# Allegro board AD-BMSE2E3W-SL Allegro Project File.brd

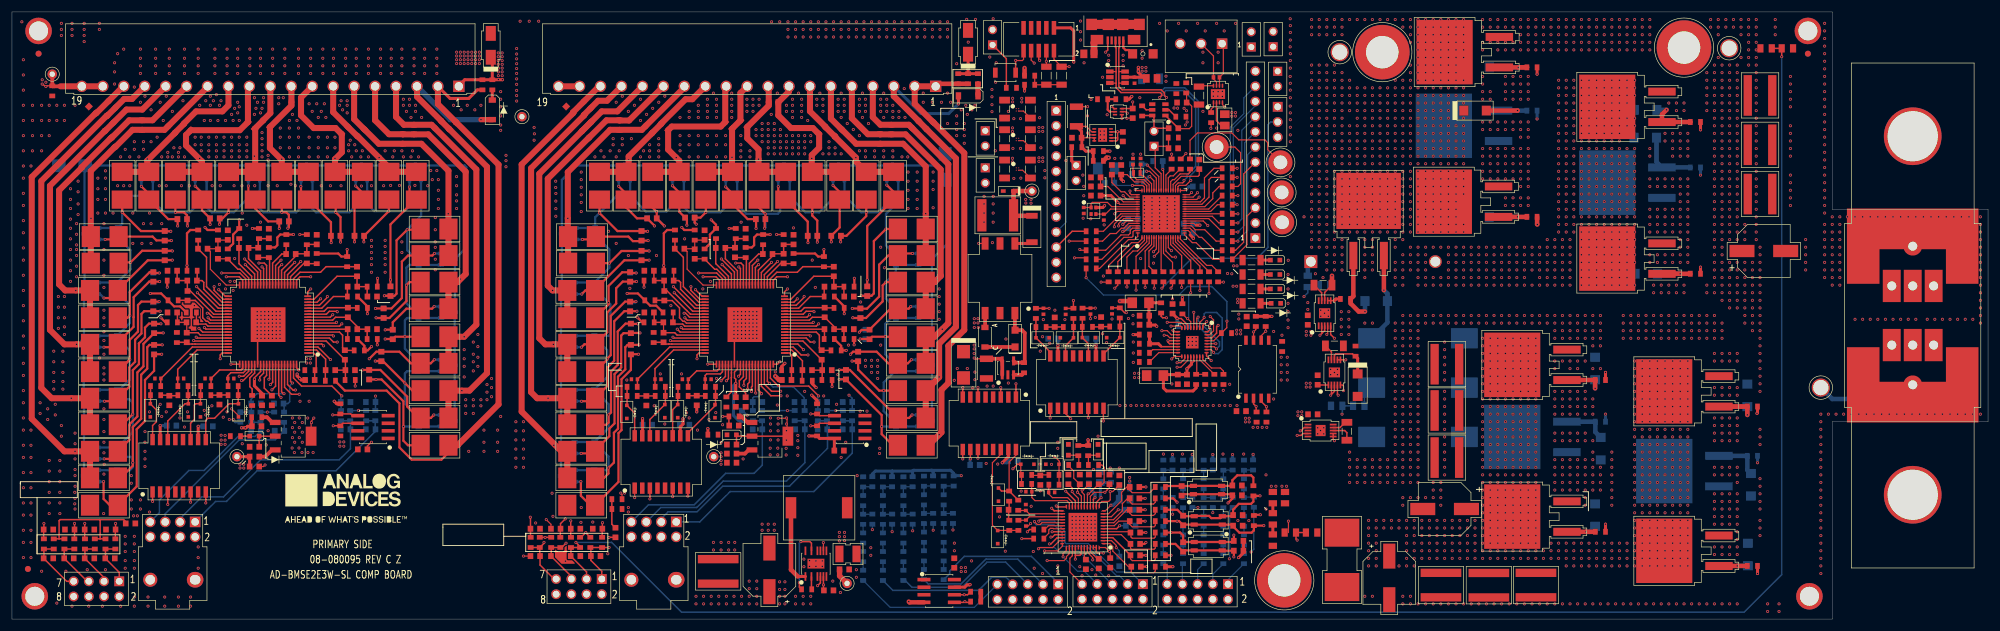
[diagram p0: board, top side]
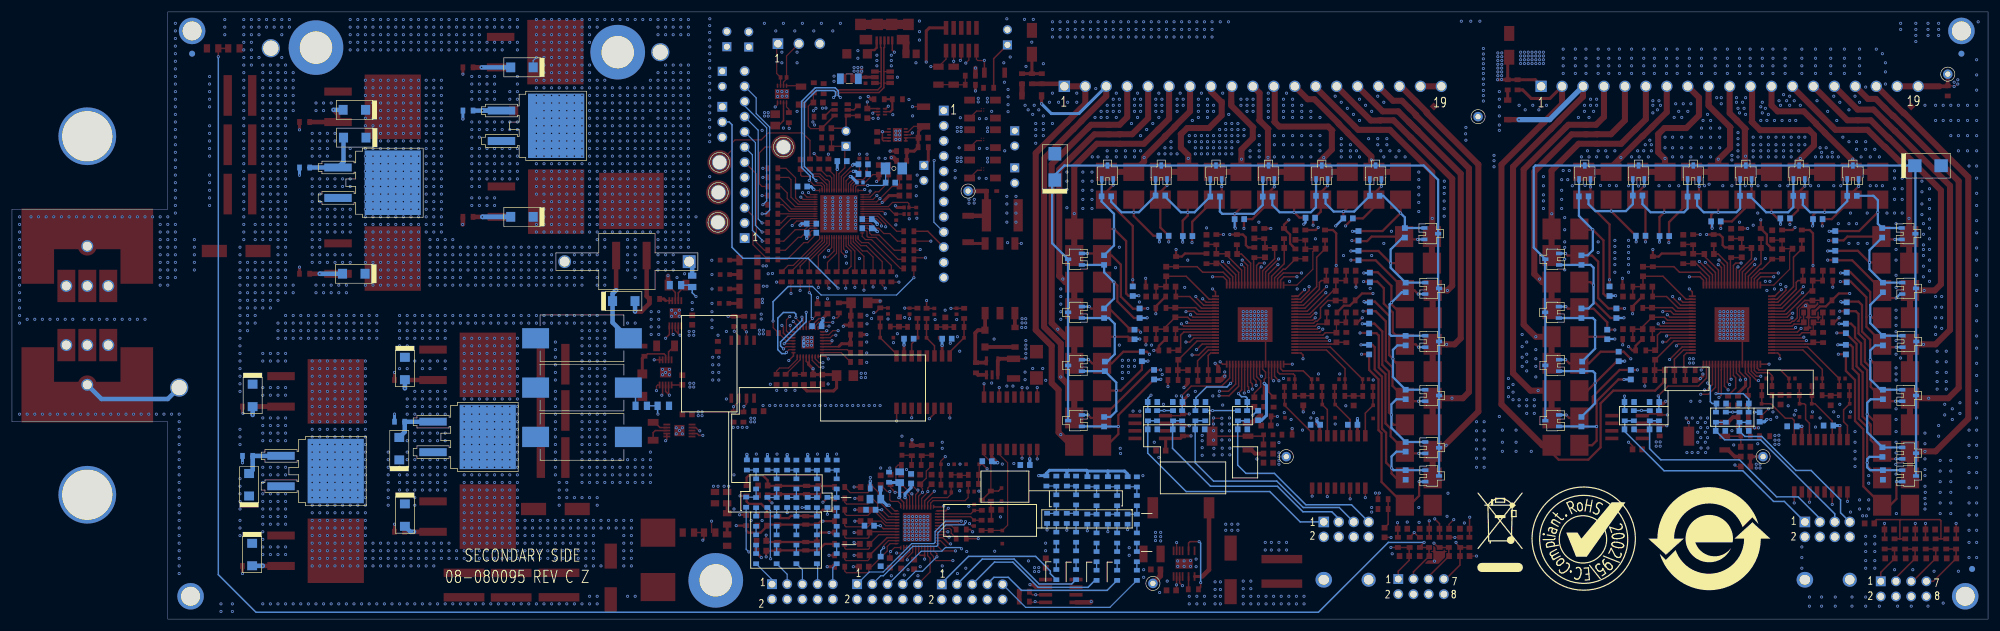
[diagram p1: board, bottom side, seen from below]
Outline 330.2 x 101.6 mm; copper layers: TOP, L2_GND, L3_SIGNAL, L4_POWER, L5_POWER, L6_SIGNAL, L7_GND, BOTTOM. Coordinates in mm from the lower left corner of the outline.
Outline path: 0,101.6 0,0 304.17,0 304.17,33.02 330.2,33.02 330.2,68.58 304.17,68.58 304.17,101.6 0,101.6

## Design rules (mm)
constraint set DEFAULT: min track width 0.203
net group USB: nets MCU_USB_DM MCU_USB_DP
net group 24MILS: nets 1V8_VDD 3V3_LDO 3V3_VDD BMS1_DRIVE BMS1_VREF2 BMS2_V- BMS2_VREF2 BMS2_VREG GND_ISO UNNAMED_16_ADP151V2_I3_VOUT VBAT+ VBUS

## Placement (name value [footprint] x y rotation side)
C1  10NF  [C0603]  73.62 82.57 225 top
C2  10NF  [C0603]  71.17 82.79 225.4 top
C3  10NF  [C0603]  67.18 81.91 270 top
C4  10NF  [C0603]  65.3 80.34 270.1 top
C5  10NF  [C0603]  58.33 81.37 225.4 top
C6  10NF  [C0603]  55.6 81.78 225.2 top
C7  10NF  [C0603]  47.5 86.49 180 top
C8  10NF  [C0603]  42.54 82.9 135.2 top
C9  10NF  [C0603]  53.21 41.66 0 top
C10  10NF  [C0603]  55.63 44.2 90 top
C11  10NF  [C0603]  56.9 48.51 0 top
C12  10NF  [C0603]  56.13 51.31 90 top
C13  10NF  [C0603]  56.9 55.63 0 top
C14  10NF  [C0603]  57.66 58.17 90 top
C15  10NF  [C0603]  49.28 60.32 90 top
C16  10NF  [C0603]  46.61 61.09 180 top
C17  0.22uF  [C0603]  59.69 40.89 90 top
C18  0.22uF  [C0603]  61.72 43.94 90 top
C19  0.22uF  [C0603]  63.63 47.62 90 top
C20  0.22uF  [C0603]  62.1 51.18 90 top
C21  0.22uF  [C0603]  63.25 54.86 90 top
C22  0.22uF  [C0603]  58.04 64.13 180 top
C23  0.22uF  [C0603]  54.1 64.13 180 top
C24  0.22uF  [C0603]  45.47 66.55 180 top
C25  10NF  [C0603]  40 82.61 135.1 top
C26  10NF  [C0603]  29.32 82.37 135.7 top
C27  10NF  [C0603]  26.67 81.91 135 top
C28  10NF  [C0603]  21.75 82.67 89.8 top
C29  10NF  [C0603]  16.09 81.14 135.1 top
C30  10NF  [C0603]  16.38 83.64 135 top
C31  10NF  [C0603]  16.72 86.15 135 top
C32  10NF  [C0603]  13.42 85.21 135 top
C33  10NF  [C0603]  41.15 61.34 90 top
C34  10NF  [C0603]  38.73 62.1 180 top
C35  10NF  [C0603]  34.42 61.09 90 top
C36  10NF  [C0603]  31.88 61.98 180 top
C37  10NF  [C0603]  30.1 56.64 180 top
C38  10NF  [C0603]  29.34 54.1 270 top
C39  10NF  [C0603]  29.97 49.66 180 top
C40  10NF  [C0603]  29.21 47.12 270 top
C41  0.22uF  [C0603]  33.91 67.06 180 top
C42  0.22uF  [C0603]  28.45 66.93 180 top
C43  0.22uF  [C0603]  25.53 64.13 270 top
C44  0.22uF  [C0603]  25.53 60.83 270 top
C45  0.22uF  [C0603]  23.62 57.28 270 top
C46  0.22uF  [C0603]  23.62 52.32 270 top
C47  0.22uF  [C0603]  23.75 48.64 270 top
C48  0.22uF  [C0603]  23.75 45.08 270 top
C49  0.22uF  [C0603]  67.95 33.02 90 bottom
C50  0.22uF  [C0603]  67.82 42.29 90 bottom
C51  0.22uF  [C0603]  67.95 51.18 90 bottom
C52  0.22uF  [C0603]  67.95 60.07 90 bottom
C53  0.22uF  [C0603]  67.56 70.74 180 bottom
C54  0.22uF  [C0603]  58.55 70.87 180 bottom
C55  0.22uF  [C0603]  49.4 70.7 180 bottom
C56  0.22uF  [C0603]  40.64 70.83 180 bottom
C57  0.22uF  [C0603]  31.74 70.83 180 bottom
C58  0.22uF  [C0603]  22.73 70.83 180 bottom
C59  0.22uF  [C0603]  17.69 64.64 270 bottom
C60  0.22uF  [C0603]  17.56 55.49 270 bottom
C61  0.22uF  [C0603]  17.56 46.6 270 bottom
C62  0.22uF  [C0603]  17.56 37.58 270 bottom
C63  0.22uF  [C0603]  17.65 27.94 270 bottom
C64  0.22uF  [C0603]  17.56 24.12 270 bottom
C65  1uF  [C0603]  43.43 36.58 270 top
C66  1uF  [C0603]  41.78 36.58 270 top
C67  10NF  [C0603]  49.78 40 180 top
C68  10NF  [C0603]  40.89 32.26 0 top
C69  0.1uF  [C0603]  58.6 28.4 0 top
C70  1uF  [C0603]  40.51 25.53 0 top
C71  0.1uF  [C0603]  59.94 36.32 180 bottom
C72  0.1uF  [C0603]  16.51 14.99 180 top
C73  0.1uF  [C0603]  55.75 36.32 0 bottom
C74  0.1uF  [C0603]  12.95 14.99 0 top
C75  0.1uF  [C0603]  44.58 36.07 180 bottom
C76  0.1uF  [C0603]  9.65 14.99 180 top
C77  0.1uF  [C0603]  40.77 36.07 0 bottom
C78  0.1uF  [C0603]  6.1 14.99 0 top
C79  10NF  [C0603]  59.94 31.75 180 bottom
C80  10NF  [C0603]  16.38 10.16 0 top
C81  10NF  [C0603]  55.75 31.75 180 bottom
C82  10NF  [C0603]  12.95 10.16 0 top
C83  10NF  [C0603]  44.7 31.5 180 bottom
C84  10NF  [C0603]  9.53 10.16 0 top
C85  10NF  [C0603]  40.77 31.5 180 bottom
C86  10NF  [C0603]  6.1 10.16 0 top
C87  300pF  [C0402]  24.38 40.26 180 top
C88  300pF  [C0402]  32.77 40.26 180 top
C89  300pF  [C0402]  28.19 40.26 0 top
C90  300pF  [C0402]  36.58 40.26 0 top
C91  0.1uF  [C0603]  26.29 36.58 270 top
C92  0.1uF  [C0603]  34.67 36.7 270 top
C93  10NF  [C0603]  26.67 32.38 0 bottom
C94  10NF  [C0603]  32.77 32.26 0 bottom
C95  10NF  [C0603]  153.38 82.57 225 top
C96  10NF  [C0603]  150.92 82.79 225.4 top
C97  10NF  [C0603]  146.94 81.91 270 top
C98  10NF  [C0603]  145.06 80.34 270.1 top
C99  10NF  [C0603]  138.09 81.37 225.4 top
C100  10NF  [C0603]  135.35 81.78 225.2 top
C101  10NF  [C0603]  127.25 86.49 180 top
C102  10NF  [C0603]  122.29 82.9 135.2 top
C103  10NF  [C0603]  132.88 41.66 0 top
C104  10NF  [C0603]  135.3 44.2 90 top
C105  10NF  [C0603]  136.57 48.51 0 top
C106  10NF  [C0603]  135.8 51.31 90 top
C107  10NF  [C0603]  136.57 55.63 0 top
C108  10NF  [C0603]  137.33 58.17 90 top
C109  10NF  [C0603]  128.95 60.32 90 top
C110  10NF  [C0603]  126.28 61.09 180 top
C111  0.22uF  [C0603]  139.36 40.89 90 top
C112  0.22uF  [C0603]  141.39 43.94 90 top
C113  0.22uF  [C0603]  143.3 47.62 90 top
C114  0.22uF  [C0603]  141.77 51.18 90 top
C115  0.22uF  [C0603]  142.92 54.86 90 top
C116  0.22uF  [C0603]  137.71 64.13 180 top
C117  0.22uF  [C0603]  133.77 64.13 180 top
C118  0.22uF  [C0603]  125.09 66.93 180 top
C119  10NF  [C0603]  119.75 82.61 135.1 top
C120  10NF  [C0603]  109.07 82.37 135.7 top
C121  10NF  [C0603]  106.43 81.91 135 top
C122  10NF  [C0603]  101.5 82.67 89.8 top
C123  10NF  [C0603]  95.85 81.14 135.1 top
C124  10NF  [C0603]  96.14 83.69 135 top
C125  10NF  [C0603]  96.12 86.05 135 top
C126  10NF  [C0603]  93.17 85.21 135 top
C127  10NF  [C0603]  120.82 61.34 90 top
C128  10NF  [C0603]  118.41 62.1 180 top
C129  10NF  [C0603]  114.09 61.09 90 top
C130  10NF  [C0603]  111.55 61.98 180 top
C131  10NF  [C0603]  109.77 56.64 180 top
C132  10NF  [C0603]  109.01 54.1 270 top
C133  10NF  [C0603]  109.64 49.66 180 top
C134  10NF  [C0603]  108.88 47.12 270 top
C135  0.22uF  [C0603]  113.28 67.18 180 top
C136  0.22uF  [C0603]  106.93 67.06 180 top
C137  0.22uF  [C0603]  105.2 64.13 270 top
C138  0.22uF  [C0603]  105.2 60.83 270 top
C139  0.22uF  [C0603]  103.29 57.28 270 top
C140  0.22uF  [C0603]  103.29 52.32 270 top
C141  0.22uF  [C0603]  103.42 48.64 270 top
C142  0.22uF  [C0603]  103.42 45.08 270 top
C143  0.22uF  [C0603]  147.7 33.02 90 bottom
C144  0.22uF  [C0603]  147.57 42.29 90 bottom
C145  0.22uF  [C0603]  147.7 51.18 90 bottom
C146  0.22uF  [C0603]  147.7 60.07 90 bottom
C147  0.22uF  [C0603]  147.32 70.74 180 bottom
C148  0.22uF  [C0603]  138.3 70.87 180 bottom
C149  0.22uF  [C0603]  129.16 70.7 180 bottom
C150  0.22uF  [C0603]  120.39 70.7 180 bottom
C151  0.22uF  [C0603]  111.5 70.83 180 bottom
C152  0.22uF  [C0603]  102.48 70.83 180 bottom
C153  0.22uF  [C0603]  97.45 64.64 270 bottom
C154  0.22uF  [C0603]  97.32 55.49 270 bottom
C155  0.22uF  [C0603]  97.32 46.6 270 bottom
C156  0.22uF  [C0603]  97.32 37.58 270 bottom
C157  0.22uF  [C0603]  97.32 28.82 270 bottom
C158  0.22uF  [C0603]  97.32 24.12 270 bottom
C159  1uF  [C0603]  122.6 36.32 270 top
C160  1uF  [C0603]  120.95 36.32 270 top
C161  10NF  [C0603]  129.45 40 180 top
C162  10NF  [C0603]  120.65 32.38 0 top
C163  0.1uF  [C0603]  138.22 28.19 0 top
C164  1uF  [C0603]  120.27 26.16 0 top
C165  0.1uF  [C0603]  139.61 36.32 180 bottom
C166  0.1uF  [C0603]  97.85 15.11 180 top
C167  0.1uF  [C0603]  135.42 36.32 0 bottom
C168  0.1uF  [C0603]  94.17 15.11 0 top
C169  0.1uF  [C0603]  131.56 36.32 180 bottom
C170  0.1uF  [C0603]  90.87 15.11 180 top
C171  0.1uF  [C0603]  124.58 36.32 0 bottom
C172  0.1uF  [C0603]  87.44 15.11 0 top
C173  10NF  [C0603]  139.61 31.75 180 bottom
C174  10NF  [C0603]  97.54 10.54 0 top
C175  10NF  [C0603]  135.42 31.75 180 bottom
C176  10NF  [C0603]  94.17 10.54 0 top
C177  10NF  [C0603]  131.69 31.75 180 bottom
C178  10NF  [C0603]  90.87 10.54 0 top
C179  10NF  [C0603]  124.58 31.75 180 bottom
C180  10NF  [C0603]  87.44 10.54 180 top
C181  10NF  [C0603]  45.47 66.55 180 bottom
C182  300pF  [C0402]  104.01 40.13 0 top
C183  300pF  [C0402]  112.52 40.13 0 top
C184  300pF  [C0402]  107.95 40.13 180 top
C185  0.1uF  [C0603]  106 36.54 270 top
C186  0.1uF  [C0603]  114.43 36.58 270 top
C187  10NF  [C0603]  106.17 32.51 0 bottom
C188  10NF  [C0603]  112.39 32.51 0 bottom
C189  10NF  [C0603]  58.04 64.13 180 bottom
C190  10NF  [C0603]  60.2 53.97 0 top
C191  10NF  [C0603]  60.2 48.51 0 top
C192  33NF  [C0805]  185.93 20.07 0 bottom
C193  33NF  [C0805]  181.86 23.75 270 bottom
C194  1uF  [C0603]  179.45 9.14 270 top
C195  1uF  [C0603]  179.96 23.49 90 bottom
C196  1uF  [C0603]  181.61 9.27 270 top
C197  22uF  [CPLSMSQ327H413]  126.57 8.23 90 top
C198  47NF  [C0603]  136.47 4.8 0 top
C199  1uF  [C1825H65]  118.01 7.98 90 top
C200  0.1uF  [C0603]  157.45 9.37 90 top
C201  100UF  [C1210H110]  139.7 10.9 0 top
C202  0.1uF  [C0603]  139.09 8.31 0 top
C203  300pF  [C0402]  169.42 18.67 90 top
C204  300pF  [C0402]  173.74 21.21 0 top
C205  300pF  [C0402]  169.44 16.06 270 top
C206  300pF  [C0402]  169.93 21.34 180 top
C207  0.1uF  [C0603]  165.74 18.29 180 top
C208  0.1uF  [C0603]  171.83 23.24 270 top
C209  10NF  [C0603]  167.26 26.42 0 bottom
C210  10NF  [C0603]  160.91 25.78 0 bottom
C211  0.1uF  [C0603]  205.41 34.8 180 top
C212  0.1uF  [C0603]  206.32 49.81 90 top
C214  4.7uF  [C1210H87]  162.84 41.91 270 top
C215  47UF  [C2220H98]  164.72 67.56 180 top
C216  10NF  [C0603]  173.96 46.91 180 bottom
C217  10NF  [C0603]  180.34 46.91 180 bottom
C218  0.1uF  [C0603]  174.24 49.68 90 top
C219  0.1uF  [C0603]  181.99 49.73 90 top
C220  300pF  [C0402]  172.36 51.51 270 top
C221  300pF  [C0402]  180.21 51.54 270 top
C222  300pF  [C0402]  176.07 51.49 270 top
C223  300pF  [C0402]  183.82 51.56 270 top
C224  0.1uF  [C0603]  189.23 49.25 180 top
C225  0.1uF  [C0603]  196.34 40.11 270 top
C226  0.1uF  [C0603]  189.23 50.77 180 top
C227  0.1uF  [C0603]  194.82 40.11 270 top
C228  0.1uF  [C0603]  193.93 51.92 90 top
C229  0.1uF  [C0603]  195.71 49.02 0 bottom
C230  22uF  [CPLSMSQ327H413]  230.15 6.88 270 top
C231  1uF  [C0603]  216.54 50.04 90 top
C232  1uF  [C1825H65]  238.79 5.69 270 top
C233  1uF  [C1825H65]  246.79 5.66 270 top
C234  0.1uF  [C1206]  223.06 31.42 270 top
C235  1uF  [C1825H65]  254.66 5.69 270 top
C236  22uF  [CPLSMSQ327H413]  239.4 18.41 180 top
C237  1uF  [C0603]  217.37 34.26 0 top
C238  1uF  [C1825H65]  239.78 34.9 180 top
C239  1uF  [C1825H65]  239.78 42.65 180 top
C240  0.1uF  [C1206]  219.08 55.88 0 top
C241  1uF  [C1825H65]  239.78 27.03 180 top
C242  22uF  [CPLSMSQ327H413]  292.74 61.59 0 top
C243  1uF  [C0603]  218.19 40 90 top
C244  1uF  [C1825H65]  292.1 79.38 0 top
C245  1uF  [C1825H65]  292.1 87.63 0 top
C246  1uF  [C1825H65]  292.1 71.12 0 top
C247  0.1uF  [C1206]  220.98 45.72 0 top
C248  0.1uF  [C0603]  187.27 84.63 90 top
C249  10uF  [C0603]  185.62 80.72 270 top
C250  0.047uF  [C1210H87]  177.88 84.1 270 top
C251  10uF  [C0603]  177.93 80.54 180 top
C252  1uF  [C1206]  165.86 85.34 270 top
C253  1uF  [C1206]  165.86 80.39 270 top
C254  1uF  [C1206]  165.86 75.31 270 top
C255  1uF  [C1206]  170.18 85.34 270 top
C256  1uF  [C1206]  170.18 80.39 270 top
C257  1uF  [C1206]  170.18 75.31 270 top
C258  0.1uF  [C0603]  183.52 9.4 270 top
C259  0.1uF  [C0603]  183.39 23.37 90 top
C260  0.1uF  [C0603]  185.04 9.65 270 bottom
C261  0.1uF  [C0603]  181.61 23.37 90 top
C262  0.1uF  [C0603]  186.69 18.29 0 bottom
C263  0.1uF  [C0603]  185.04 23.24 90 top
C264  0.1uF  [C0603]  179.96 23.37 90 top
C265  0.1uF  [C0603]  178.44 23.37 90 top
C266  0.1uF  [C0603]  186.94 15.62 0 bottom
C267  0.1uF  [C0603]  176.53 23.37 90 top
C268  2.2uF  [C0805H53]  202.67 83.54 90 top
C269  1uF  [C0603]  181.1 72.39 180 top
C270  0.1uF  [C0603]  181.1 73.91 180 top
C271  0.1uF  [C0603]  181.1 70.87 180 top
C272  1uF  [C0603]  198.4 76.1 90 top
C273  1uF  [C0603]  185.34 75.18 90 top
C274  4.7NF  [C0402]  188.49 73.08 0 bottom
C275  1uF  [C0603]  183.41 73.02 0 bottom
C276  1uF  [C0603]  191.49 76.63 180 bottom
C277  1uF  [C0603]  187.96 76.1 180 bottom
C278  1uF  [C0603]  198.12 72.39 0 bottom
C279  1uF  [C0603]  187.93 74.47 180 bottom
C280  10uF  [C1206H71]  182.83 75.41 0 bottom
C281  1uF  [C0603]  196.6 66.17 0 bottom
C282  1uF  [C0603]  196.6 64.64 0 bottom
C283  1uF  [C0603]  187.33 66.93 180 bottom
C284  1uF  [C0603]  187.33 65.4 180 bottom
C285  1uF  [C0603]  183.79 75.18 270 top
C286  1uF  [C0603]  194.06 78.79 0 top
C287  0.1uF  [C1206]  190.27 90.42 180 bottom
C288  1UF  [C0805H55]  190.45 90.47 180 top
C289  0.1uF  [C0603]  194.09 82.14 180 top
C290  10NF  [C0402]  187.58 90.17 90 top
C291  0.1uF  [C0603]  195.49 86.44 180 top
C292  12pF  [C0402]  188.6 76.58 270 top
C293  12pF  [C0402]  179.1 68.38 90 top
C294  12pF  [C0402]  187.33 76.58 270 top
C295  12pF  [C0402]  182.45 67.26 90 top
C296  10NF  [C0603]  63.63 47.62 90 bottom
C297  10NF  [C0603]  62.1 51.18 90 bottom
C298  10NF  [C0603]  59.69 40.89 90 bottom
C299  10NF  [C0603]  56.52 41.66 0 top
C300  10NF  [C0603]  61.72 43.94 90 bottom
C301  10NF  [C0603]  63.25 54.86 90 bottom
C302  10NF  [C0603]  50.93 63.5 90 top
C303  10NF  [C0603]  54.08 64.1 180 bottom
C304  10NF  [C0603]  26.8 51.31 180 top
C305  10NF  [C0603]  23.75 45.08 270 bottom
C306  10NF  [C0603]  25.53 60.83 270 bottom
C307  10NF  [C0603]  36.07 64.26 90 top
C308  10NF  [C0603]  25.53 64.13 270 bottom
C309  10NF  [C0603]  23.75 48.64 270 bottom
C310  10NF  [C0603]  23.62 52.2 270 bottom
C311  10NF  [C0603]  26.8 58.29 180 top
C312  10NF  [C0603]  28.45 66.93 180 bottom
C313  10NF  [C0603]  23.62 57.15 270 bottom
C314  10NF  [C0603]  42.93 64.52 90 top
C315  10NF  [C0603]  33.91 67.06 180 bottom
C316  10NF  [C0603]  40.51 28.83 0 top
C317  10NF  [C0603]  139.36 40.89 90 bottom
C318  10NF  [C0603]  136.19 41.66 0 top
C319  10NF  [C0603]  141.39 43.94 90 bottom
C320  10NF  [C0603]  139.87 48.51 0 top
C321  10NF  [C0603]  141.77 51.18 90 bottom
C322  10NF  [C0603]  133.75 64.1 180 bottom
C323  10NF  [C0603]  130.6 63.5 90 top
C324  10NF  [C0603]  125.09 66.93 180 bottom
C325  10NF  [C0603]  142.92 54.86 90 bottom
C326  10NF  [C0603]  139.87 53.97 0 top
C327  10NF  [C0603]  137.71 64.13 180 bottom
C328  10NF  [C0603]  142.62 47.62 90 bottom
C329  10NF  [C0603]  113.25 67.15 180 bottom
C330  10NF  [C0603]  122.6 64.52 90 top
C331  10NF  [C0603]  106.93 67.06 180 bottom
C332  10NF  [C0603]  103.29 52.2 270 bottom
C333  10NF  [C0603]  106.47 51.31 180 top
C334  10NF  [C0603]  103.42 45.08 270 bottom
C335  10NF  [C0603]  105.2 64.13 270 bottom
C336  300pF  [C0402]  116.33 40.13 180 top
C337  10NF  [C0603]  103.29 57.15 270 bottom
C338  10NF  [C0603]  106.47 58.29 180 top
C339  10NF  [C0603]  103.42 48.64 270 bottom
C340  10NF  [C0603]  115.74 64.26 90 top
C341  10NF  [C0603]  105.2 60.83 270 bottom
C342  10NF  [C0603]  120.27 29.21 0 top
C343  0.22uF  [C0603]  187.71 12.57 180 top
C344  0.22uF  [C0603]  187.58 22.1 180 top
C345  0.22uF  [C0603]  187.58 18.29 180 top
C346  0.22uF  [C0603]  204.85 17.4 0 top
C347  0.22uF  [C0603]  204.72 22.35 180 top
C348  0.22uF  [C0603]  204.98 11.43 0 top
C349  0.22uF  [C0603]  195.45 21.46 90 top
C350  0.22uF  [C0603]  195.71 16.51 90 top
C351  0.22uF  [C0603]  195.71 12.06 270 top
C352  0.22uF  [C0603]  204.98 13.08 0 top
C353  0.22uF  [C0603]  204.72 20.7 180 top
C354  0.22uF  [C0603]  204.85 15.62 0 top
C355  0.22uF  [C0603]  187.83 8.76 180 top
C356  0.22uF  [C0603]  187.58 16.38 180 top
C357  0.22uF  [C0603]  187.71 10.67 180 top
C358  0.22uF  [C0603]  187.58 20.19 180 top
C359  0.22uF  [C0603]  187.71 14.48 180 top
D1  SD12C-01FTG  [SOD323-5]  23.11 34.92 90 top
D2  SD12C-01FTG  [SOD323-5]  31.5 34.92 90 top
D3  SD12C-01FTG  [SOD323-5]  29.46 34.92 90 top
D4  SD12C-01FTG  [SOD323-5]  37.85 34.92 90 top
D5  SD12C-01FTG  [SOD323-5]  102.74 34.67 90 top
D6  SD12C-01FTG  [SOD323-5]  111.25 34.8 90 top
D7  SD12C-01FTG  [SOD323-5]  109.09 34.8 90 top
D8  SD12C-01FTG  [SOD323-5]  117.47 34.8 90 top
D9  SD12C-01FTG  [SOD323-5]  164.85 20.83 90 top
D10  SD12C-01FTG  [SOD323-5]  173.86 25.91 0 top
D11  SD12C-01FTG  [SOD323-5]  164.72 13.72 90 top
D12  SD12C-01FTG  [SOD323-5]  169.67 25.91 180 top
D13  SD12C-01FTG  [SOD323-5]  172.21 47.07 180 top
D14  SD12C-01FTG  [SOD323-5]  179.96 47.09 180 top
D15  SD12C-01FTG  [SOD323-5]  176.28 47.07 0 top
D16  SD12C-01FTG  [SOD323-5]  184.02 47.09 0 top
D17  TPSMF4L28A  [SOD123FL]  162.59 47.17 90 top
D18  PMEG10010ELRX  [SOD123F]  167.61 46.94 90 top
D19  PMEG6030EP,115  [SOD128]  170.43 65.28 270 top
D20  EDZVFHT2R15B  [SOD523_B]  166.5 71.63 180 top
D21  1N4148W-7-F  [SOD123-2]  80.26 85.22 270 top
D22  SMAT70A-13-F  [SMA-2]  80.01 96.01 90 top
D23  SMAT70A-13-F  [SMA-2]  159.77 96.52 90 top
D24  1N4148W-7-F  [SOD123-2]  159.79 87.55 180 top
D25  SBAV70LT3G  [SOT23_B]  40.46 74.75 180 bottom
D26  SBAV70LT3G  [SOT23_B]  49.25 74.75 180 bottom
D27  SBAV70LT3G  [SOT23_B]  58.39 74.75 180 bottom
D28  SBAV70LT3G  [SOT23_B]  67.39 74.75 180 bottom
D29  SBAV70LT3G  [SOT23_B]  72.82 60.22 90 bottom
D30  SBAV70LT3G  [SOT23_B]  72.87 51.33 90 bottom
D31  SBAV70LT3G  [SOT23_B]  72.82 42.44 90 bottom
D32  SBAV70LT3G  [SOT23_B]  72.82 33.2 90 bottom
D33  SMBJ75A-13-F  [DO214AA_A]  10.03 75.87 180 bottom
D34  SBAV70LT3G  [SOT23_B]  13.18 55.35 270 bottom
D35  SBAV70LT3G  [SOT23_B]  13.13 46.46 270 bottom
D36  SBAV70LT3G  [SOT23_B]  13.18 23.95 270 bottom
D37  SBAV70LT3G  [SOT23_B]  31.57 74.75 180 bottom
D38  SBAV70LT3G  [SOT23_B]  22.58 74.75 180 bottom
D39  SBAV70LT3G  [SOT23_B]  13.18 37.41 270 bottom
D40  SBAV70LT3G  [SOT23_B]  13.28 64.49 270 bottom
D41  SBAV70LT3G  [SOT23_B]  13.18 27.76 270 bottom
D42  SBAV70LT3G  [SOT23_B]  120.22 74.75 180 bottom
D43  SBAV70LT3G  [SOT23_B]  129.01 74.75 180 bottom
D44  SBAV70LT3G  [SOT23_B]  138.15 74.75 180 bottom
D45  SBAV70LT3G  [SOT23_B]  147.14 74.75 180 bottom
D46  SBAV70LT3G  [SOT23_B]  152.58 60.22 90 bottom
D47  SBAV70LT3G  [SOT23_B]  152.58 51.33 90 bottom
D48  SBAV70LT3G  [SOT23_B]  152.58 42.44 90 bottom
D49  SBAV70LT3G  [SOT23_B]  152.58 33.2 90 bottom
D50  SMBJ75A-13-F  [DO214AA_A]  155.93 75.67 90 bottom
D51  SBAV70LT3G  [SOT23_B]  92.89 55.35 270 bottom
D52  SBAV70LT3G  [SOT23_B]  92.89 23.95 270 bottom
D53  SBAV70LT3G  [SOT23_B]  111.33 74.75 180 bottom
D54  SBAV70LT3G  [SOT23_B]  92.89 46.46 270 bottom
D55  SBAV70LT3G  [SOT23_B]  92.89 28.68 270 bottom
D56  SBAV70LT3G  [SOT23_B]  102.34 74.75 180 bottom
D57  SBAV70LT3G  [SOT23_B]  93.04 64.49 270 bottom
D58  SBAV70LT3G  [SOT23_B]  92.89 37.41 270 bottom
D59  SMAJ7.0A  [DO214AC_A]  265.49 28.52 90 bottom
D60  SMAJ7.0A  [DO214AC_A]  264.54 17.4 270 bottom
D61  SMAJ7.0A  [DO214AC_A]  227.97 53.21 180 bottom
D62  SMAJ7.0A  [DO214AC_A]  264.54 41.93 270 bottom
D63  SMAJ7.0A  [DO214AC_A]  244.98 67.31 0 bottom
D64  SMAJ7.0A  [DO214AC_A]  244.48 85.09 0 top
D65  SMAJ7.0A  [DO214AC_A]  244.98 92.33 0 bottom
D66  SMBJ75A-13-F  [DO214AA_A]  159 42.54 270 top
D67  30KPA120CA  [DTH819L350W350LD52_BIDIR]  217.04 59.82 0 bottom
D68  SMAJ7.0A  [DO214AC_A]  289.98 37.43 270 bottom
D69  SMAJ7.0A  [DO214AC_A]  290.58 22.48 90 bottom
D70  SMAJ7.0A  [DO214AC_A]  290.07 10.79 270 bottom
D71  SMAJ7.0A  [DO214AC_A]  272.92 80.57 0 bottom
D72  SMAJ7.0A  [DO214AC_A]  272.98 85.22 0 bottom
D73  SMAJ7.0A  [DO214AC_A]  273.08 57.78 0 bottom
D74  SMAJ7.0A  [DO214AC_A]  224.87 39.14 270 top
DS1  SML-D13FWT86C  [LED0603-2]  40.51 30.61 180 top
DS2  SML-D13FWT86C  [LED0603-2]  120.27 30.84 180 top
DS3  SML-D13FWT86C  [LED0603-2]  211.07 60.07 180 top
DS4  SML-D13FWT86C  [LED0603-2]  211.07 57.66 180 top
DS5  SML-D13FWT86C  [LED0603-2]  211.2 52.83 180 top
DS6  SML-D13FWT86C  [LED0603-2]  211.07 55.24 180 top
E1  2.2KOHM AT 100MEGHZ  [L0603]  40.51 27.18 180 top
E2  2.2KOHM AT 100MEGHZ  [L0603]  38.17 33.81 90 bottom
E3  2.2KOHM AT 100MEGHZ  [L0603]  19.81 16 180 top
E4  2.2KOHM AT 100MEGHZ  [L0603]  120.27 27.69 180 top
E5  2.2KOHM AT 100MEGHZ  [L0603]  121.98 34.06 90 bottom
E6  2.2KOHM AT 100MEGHZ  [L0603]  100.84 14.48 270 top
E7  1KOHM AT 100MEGHZ  [L1206-3]  188.6 52.93 0 top
E8  1KOHM AT 100MEGHZ  [L1206-3]  191.01 40.74 0 top
F1  100A  [FSML484W177H185]  222.25 9.91 90 top
L1  220UH  [LSML402W394H201]  134.87 18.62 0 top
L2  2000OHMS  [L1206]  188.98 94.59 180 top
L3  4.7uH  [L0805]  179.96 94.59 0 top
L4  200UH  [LSML177W126H114]  199.77 21.59 0 top
L5  200UH  [LSML177W126H114]  199.9 16.51 0 top
L6  200UH  [LSML177W126H114]  199.9 12.19 180 top
NOREF  -  []  -221.61 -349.88 0 top
NOREF#2  -  []  304.17 0 90 top
NOREF#3  -  []  311.12 68.58 90 top
NOREF#4  -  []  55.24 20.19 0 top
NOREF#5  -  []  -221.61 -349.88 0 top
NOREF#6  -  []  0 65.24 0 top
NOREF#7  -  []  124.46 -78.61 0 top
NOREF#8  -  []  0 0 0 top
NOREF#9  -  []  304.17 81.48 0 top
NOREF#10  -  [unnamed#2]  300.1 94.62 0 top
NOREF#11  -  []  -144.14 127 0 top
NOREF#12  -  []  -1.65 -30.35 0 top
NOREF#13  -  [unnamed#2]  300.1 98.43 0 top
NOREF#14  -  [unnamed#2]  4.45 98.43 0 top
NOREF#15  -  []  132.08 160.02 0 top
NOREF#16  -  []  4.79 0 90 top
NOREF#17  -  []  301.94 0 90 top
NOREF#18  -  []  202.99 100.96 0 top
NOREF#19  -  []  304.17 101.6 180 top
NOREF#20  -  [unnamed#2]  2.67 8.38 0 top
NOREF#21  -  []  328.17 33.02 90 top
NOREF#22  -  []  -140.44 104.14 0 top
NOREF#23  -  [unnamed#2]  4.45 94.62 0 top
NOREF#24  -  [unnamed#2]  3.81 3.81 0 top
NOREF#25  -  []  330.2 33.02 90 top
NOREF#26  -  []  -221.61 -349.88 0 top
NOREF#27  -  []  -140.39 81.28 0 top
NOREF#28  -  []  90.68 112.27 0 top
NOREF#29  -  []  330.2 68.58 180 top
NOREF#30  -  []  0 101.6 270 top
NOREF#31  -  []  0 101.13 0 top
NOREF#32  -  [unnamed#2]  300.36 3.81 0 top
NOREF#33  -  [unnamed#2]  4.45 94.62 180 bottom
NOREF#34  -  []  72.26 24.76 180 bottom
NOREF#35  -  [unnamed#2]  2.67 8.38 180 bottom
NOREF#36  -  []  67.56 13.33 180 bottom
NOREF#37  -  []  46.61 13.46 180 bottom
NOREF#38  -  [unnamed#2]  300.1 94.62 180 bottom
P1  1841800000  [CNTHMHDRRA1X19L2673W437H295]  74.68 89.15 180 top
P2  1053141308  [CNMOLEX1053141308]  30.61 16.26 180 top
P3  TSW-104-07-G-D  [CNTHMHDR2X4L400W200H330]  17.92 6.32 180 top
P4  1841800000  [CNTHMHDRRA1X19L2673W437H295]  154.35 89.15 180 top
P5  1053141308  [CNMOLEX1053141308]  111 16.26 180 top
P6  TSW-104-07-G-D  [CNTHMHDR2X4L400W200H330]  98.55 6.7 180 top
P7  TSW-105-08-G-D  [CNSAMTEC2X5H338LD36]  203.2 5.84 180 top
P8  TSW-105-08-G-D  [CNSAMTEC2X5H338LD36]  174.82 5.81 180 top
P9  TSW-105-08-G-D  [CNSAMTEC2X5H338LD36]  188.98 5.84 180 top
P10  OSTTF030161  [CNOSTTF030161]  202.21 96.29 180 top
P11  ZX62-AB-5PA(31)  [CNHRSZX62-B-5PA_6SHLD]  184.4 99.51 180 top
P12  3220-10-0300-00  [CNSMMHDR2X5L443W201H228]  171.58 97.03 180 top
P13  TSW-112-16-G-S  [CNHDR1X12H420]  207.77 63.75 90 top
P14  TSW-112-16-G-S  [CNHDR1X12H420]  174.5 85.09 270 top
P15  69157-102HLF  [CNBERG69157-102]  207.09 95.73 90 top
P16  69157-102HLF  [CNBERG69157-102]  177.83 75.92 270 top
P17  69157-102HLF  [CNBERG69157-102]  162.64 75.51 270 top
P18  69157-102HLF  [CNBERG69157-102]  162.64 81.71 270 top
P19  69157-102HLF  [CNBERG69157-102]  163.86 96.09 90 top
P20  M20-9990345  [CNHDR1X3H340]  211.51 85.72 270 top
P21  69157-102HLF  [CNBERG69157-102]  211.51 91.67 270 top
P22  69157-102HLF  [CNBERG69157-102]  210.74 95.78 90 top
P23  69157-102HLF  [CNBERG69157-102]  190.83 79.12 90 top
Q1  BCP56-16TF  [SOT223_A]  46.99 30.61 270 top
Q2  BCP56-16TF  [SOT223_A]  126.66 30.61 270 top
Q3  IPB048N15N5LFATMA1  [TO263-3]  255.27 30.48 270 bottom
Q4  IPB048N15N5LFATMA1  [TO263-3]  255.27 17.14 90 top
Q5  IPB048N15N5LFATMA1  [TO263-3]  243.84 69.85 90 top
Q6  IPB048N15N5LFATMA1  [TO263-3]  255.27 42.54 90 top
Q7  IPB048N15N5LFATMA1  [TO263-3]  226.7 65.4 0 top
Q8  IPB048N15N5LFATMA1  [TO263-3]  243.84 82.55 270 bottom
Q9  IPB048N15N5LFATMA1  [TO263-3]  243.97 94.87 90 top
Q10  IPB048N15N5LFATMA1  [TO263-3]  280.67 38.1 90 top
Q11  IPB048N15N5LFATMA1  [TO263-3]  280.67 24.76 270 bottom
Q12  IPB048N15N5LFATMA1  [TO263-3]  280.67 11.43 90 top
Q13  IPB048N15N5LFATMA1  [TO263-3]  271.15 73.02 270 bottom
Q14  IPB048N15N5LFATMA1  [TO263-3]  271.15 85.72 90 top
Q15  IPB048N15N5LFATMA1  [TO263-3]  271.15 60.32 90 top
R1  200  [R0603]  80.26 89.41 90 top
R2  200  [R0603]  53.21 39.88 180 top
R3  200  [R0603]  56.52 40 180 top
R4  200  [R0603]  58.04 44.96 180 top
R5  200  [R0603]  56.9 46.86 180 top
R6  200  [R0603]  60.2 46.86 180 top
R7  200  [R0603]  58.55 52.07 180 top
R8  200  [R0603]  56.9 53.97 180 top
R9  200  [R0603]  60.2 55.63 180 top
R10  200  [R0603]  56.01 59.82 270 top
R11  200  [R0603]  50.93 60.32 270 top
R12  200  [R0603]  49.28 63.5 270 top
R13  200  [R0603]  45.85 63.5 270 top
R14  15  [R2512-2]  70.61 29.08 180 top
R15  15  [R2512-2]  70.61 33.65 180 top
R16  15  [R2512-2]  70.61 38.23 180 top
R17  15  [R2512-2]  70.61 42.8 180 top
R18  15  [R2512-2]  70.61 47.24 180 top
R19  15  [R2512-2]  70.61 51.94 180 top
R20  15  [R2512-2]  70.61 56.39 180 top
R21  15  [R2512-2]  70.61 60.83 180 top
R22  15  [R2512-2]  70.61 65.28 180 top
R23  15  [R2512-2]  67.56 72.52 270 top
R24  15  [R2512-2]  62.99 72.52 270 top
R25  15  [R2512-2]  58.55 72.52 270 top
R26  15  [R2512-2]  53.98 72.52 270 top
R27  15  [R2512-2]  49.53 72.52 270 top
R28  15  [R2512-2]  45.09 72.52 270 top
R29  15  [R2512-2]  40.64 72.52 270 top
R30  200  [R0603]  42.93 61.34 270 top
R31  200  [R0603]  41.27 64.52 270 top
R32  200  [R0603]  37.97 64.52 270 top
R33  200  [R0603]  36.07 61.09 270 top
R34  200  [R0603]  34.42 64.26 270 top
R35  200  [R0603]  31.11 64.26 270 top
R36  200  [R0603]  30.1 58.29 0 top
R37  200  [R0603]  26.8 56.64 0 top
R38  200  [R0603]  26.92 53.34 0 top
R39  200  [R0603]  29.97 51.31 0 top
R40  200  [R0603]  26.8 49.66 0 top
R41  200  [R0603]  27.56 47.12 270 top
R42  15  [R2512-2]  36.2 72.52 270 top
R43  15  [R2512-2]  31.75 72.52 270 top
R44  15  [R2512-2]  27.3 72.52 270 top
R45  15  [R2512-2]  22.86 72.52 270 top
R46  15  [R2512-2]  18.41 72.52 270 top
R47  15  [R2512-2]  15.49 64.01 0 top
R48  15  [R2512-2]  15.49 59.56 0 top
R49  15  [R2512-2]  15.37 54.99 0 top
R50  15  [R2512-2]  15.37 50.42 0 top
R51  15  [R2512-2]  15.37 45.97 0 top
R52  15  [R2512-2]  15.37 41.4 0 top
R53  15  [R2512-2]  15.37 36.96 0 top
R54  15  [R2512-2]  15.37 32.51 0 top
R55  15  [R2512-2]  15.37 28.07 0 top
R56  15  [R2512-2]  15.37 23.62 0 top
R57  15  [R2512-2]  15.37 19.05 0 top
R58  1K  [R0603]  49.78 41.66 0 top
R59  330  [R0603]  37.34 30.61 0 top
R60  3.3K  [R0603]  54.86 31.5 90 top
R61  10  [R0603]  40.89 33.78 0 top
R62  3.3K  [R0603]  54.86 35.18 270 top
R63  1K  [R0603]  60.71 34.04 270 bottom
R64  0  [R0603]  17.27 12.57 270 top
R65  1K  [R0603]  54.99 34.04 270 bottom
R66  0  [R0603]  12.19 12.57 270 top
R67  1K  [R0603]  45.47 33.78 270 bottom
R68  0  [R0603]  10.41 12.57 270 top
R69  1K  [R0603]  40.01 33.78 270 bottom
R70  0  [R0603]  5.33 12.57 270 top
R71  10K  [R0603]  59.18 34.04 270 bottom
R72  3.3K  [R0603]  15.62 12.57 270 top
R73  10K  [R0603]  56.52 34.04 270 bottom
R74  3.3K  [R0603]  13.84 12.57 270 top
R75  10K  [R0603]  43.81 33.78 270 bottom
R76  3.3K  [R0603]  8.76 12.57 270 top
R77  10K  [R0603]  41.53 33.78 270 bottom
R78  3.3K  [R0603]  6.99 12.57 270 top
R79  22  [R0603]  24 38.99 180 top
R80  22  [R0603]  32.38 38.99 180 top
R81  22  [R0603]  28.57 38.99 0 top
R82  22  [R0603]  36.96 38.99 0 top
R83  51  [R0603]  24 37.46 0 top
R84  51  [R0603]  32.38 37.46 0 top
R85  51  [R0603]  28.57 37.46 180 top
R86  51  [R0603]  36.96 37.46 180 top
R87  200  [R0603]  132.88 39.88 180 top
R88  200  [R0603]  136.19 40 180 top
R89  200  [R0603]  137.71 44.96 180 top
R90  200  [R0603]  136.57 46.86 180 top
R91  200  [R0603]  139.87 46.86 180 top
R92  200  [R0603]  138.22 52.07 180 top
R93  200  [R0603]  136.57 53.97 180 top
R94  200  [R0603]  139.87 55.63 180 top
R95  200  [R0603]  135.68 59.82 270 top
R96  200  [R0603]  130.6 60.32 270 top
R97  200  [R0603]  128.95 63.5 270 top
R98  200  [R0603]  125.52 63.5 270 top
R99  15  [R2512-2]  150.37 29.08 180 top
R100  15  [R2512-2]  150.37 33.65 180 top
R101  15  [R2512-2]  150.37 38.23 180 top
R102  15  [R2512-2]  150.37 42.8 180 top
R103  15  [R2512-2]  150.37 47.24 180 top
R104  15  [R2512-2]  150.37 51.94 180 top
R105  15  [R2512-2]  150.37 56.39 180 top
R106  15  [R2512-2]  150.37 60.83 180 top
R107  15  [R2512-2]  150.37 65.28 180 top
R108  15  [R2512-2]  147.32 72.52 270 top
R109  15  [R2512-2]  142.75 72.52 270 top
R110  15  [R2512-2]  138.3 72.52 270 top
R111  15  [R2512-2]  133.73 72.52 270 top
R112  15  [R2512-2]  129.29 72.52 270 top
R113  15  [R2512-2]  124.84 72.52 270 top
R114  15  [R2512-2]  120.4 72.52 270 top
R115  200  [R0603]  122.6 61.34 270 top
R116  200  [R0603]  120.95 64.52 270 top
R117  200  [R0603]  117.64 64.52 270 top
R118  200  [R0603]  115.74 61.09 270 top
R119  200  [R0603]  114.09 64.26 270 top
R120  200  [R0603]  110.79 64.26 270 top
R121  200  [R0603]  109.77 58.29 0 top
R122  200  [R0603]  106.47 56.64 0 top
R123  200  [R0603]  106.59 53.34 0 top
R124  200  [R0603]  109.64 51.31 0 top
R125  200  [R0603]  106.47 49.66 0 top
R126  200  [R0603]  107.23 47.12 270 top
R127  15  [R2512-2]  115.95 72.52 270 top
R128  15  [R2512-2]  111.51 72.52 270 top
R129  15  [R2512-2]  107.06 72.52 270 top
R130  15  [R2512-2]  102.62 72.52 270 top
R131  15  [R2512-2]  98.17 72.52 270 top
R132  15  [R2512-2]  95.25 64.01 0 top
R133  15  [R2512-2]  95.25 59.56 0 top
R134  15  [R2512-2]  95.12 54.99 0 top
R135  15  [R2512-2]  95.12 50.42 0 top
R136  15  [R2512-2]  95.12 45.97 0 top
R137  15  [R2512-2]  95.12 41.4 0 top
R138  15  [R2512-2]  95.12 36.96 0 top
R139  15  [R2512-2]  95.12 32.51 0 top
R140  15  [R2512-2]  95.12 28.07 0 top
R141  15  [R2512-2]  95.12 23.62 0 top
R142  15  [R2512-2]  95.12 19.05 0 top
R143  1K  [R0603]  129.45 41.66 0 top
R144  330  [R0603]  117.14 30.86 0 top
R145  3.3K  [R0603]  134.53 31.5 90 top
R146  10  [R0603]  120.65 33.91 0 top
R147  3.3K  [R0603]  134.53 35.18 270 top
R148  1K  [R0603]  140.38 34.04 270 bottom
R149  0  [R0603]  98.61 12.83 270 top
R150  1K  [R0603]  134.66 34.04 270 bottom
R151  0  [R0603]  93.41 12.83 270 top
R152  1K  [R0603]  132.45 34.04 270 bottom
R153  0  [R0603]  91.63 12.83 270 top
R154  1K  [R0603]  123.82 34.04 270 bottom
R155  0  [R0603]  86.67 12.83 270 top
R156  10K  [R0603]  138.85 34.04 270 bottom
R157  10K  [R0603]  96.65 12.83 270 top
R158  10K  [R0603]  136.19 34.04 270 bottom
R159  10K  [R0603]  94.93 12.83 270 top
R160  10K  [R0603]  130.8 34.04 270 bottom
R161  10K  [R0603]  90.1 12.83 270 top
R162  10K  [R0603]  125.34 34.04 270 bottom
R163  10K  [R0603]  88.2 12.83 270 top
R164  22  [R0603]  103.63 38.86 180 top
R165  22  [R0603]  112.14 38.86 180 top
R166  22  [R0603]  108.33 38.86 0 top
R167  22  [R0603]  116.71 38.86 0 top
R168  51  [R0603]  103.63 37.34 0 top
R169  51  [R0603]  112.14 37.34 0 top
R170  51  [R0603]  108.33 37.34 180 top
R171  51  [R0603]  116.71 37.34 180 top
R172  10K  [R0603]  179.83 28.19 90 top
R173  1K  [R0603]  180.72 25.78 0 top
R174  120  [R0603]  191.9 12.57 0 top
R175  120  [R0603]  191.9 22.1 0 top
R176  120  [R0603]  191.9 18.29 0 top
R177  1.24MEG  [R0805]  210.69 13.21 90 top
R178  1.24MEG  [R0805]  210.69 16.76 90 top
R179  1.24MEG  [R0805]  210.69 20.32 90 top
R180  100K  [R0805]  212.73 20.32 270 top
R181  1K  [R0603]  177.42 25.78 0 top
R182  0  [R0603]  207.44 21.46 90 top
R183  10K  [R0603]  178.18 28.19 90 top
R184  1K  [R0603]  185.93 21.84 180 bottom
R185  1K  [R0603]  183.64 23.75 270 bottom
R186  3.3K  [R0603]  161.04 4.57 180 top
R187  2MEG  [R0603]  132.79 4.98 180 top
R188  3.3K  [R0603]  161.04 2.92 180 top
R189  22  [R0603]  168.15 19.05 90 top
R190  22  [R0603]  174.12 22.48 0 top
R191  22  [R0603]  168.17 15.68 270 top
R192  22  [R0603]  169.55 22.61 180 top
R193  51  [R0603]  166.62 20.57 270 top
R194  51  [R0603]  174.12 24.13 180 top
R195  51  [R0603]  166.65 15.68 90 top
R196  51  [R0603]  169.55 24.13 0 top
R197  10K  [R0603]  207.98 33.81 90 top
R198  10K  [R0603]  209.63 33.81 90 top
R199  10K  [R0603]  207.85 49.81 270 top
R200  10K  [R0603]  209.5 49.81 270 top
R201  316K  [R0603]  169.11 42.06 90 top
R202  51  [R0603]  171.96 48.87 0 top
R203  51  [R0603]  179.71 48.89 0 top
R204  22  [R0603]  171.09 51.16 90 top
R205  22  [R0603]  178.89 51.18 90 top
R206  51  [R0603]  176.53 48.87 180 top
R207  51  [R0603]  184.28 48.95 180 top
R208  22  [R0603]  177.37 51.16 90 top
R209  22  [R0603]  185.12 51.23 90 top
R210  0  [R0603]  189.23 47.6 0 top
R211  0  [R0603]  189.23 46.08 180 top
R212  0  [R0603]  197.87 40.11 90 top
R213  0  [R0603]  199.39 40.11 270 top
R214  20K  [R0603]  189.23 43.03 180 top
R215  20K  [R0603]  202.44 40.11 270 top
R216  0  [R0603]  189.23 44.55 180 top
R217  0  [R0603]  200.91 40.11 270 top
R218  0  [R0603]  212.24 45.62 270 top
R219  0  [R0603]  195.3 76.15 270 top
R220  0  [R0603]  196.85 76.15 270 top
R221  10  [R0603]  265.43 14.6 0 top
R222  10  [R0603]  265.43 40 0 top
R223  10  [R0603]  254 85.09 0 bottom
R224  10K  [R0603]  195.58 51.92 270 top
R225  10K  [R0603]  202.95 47.85 180 top
R226  10  [R0603]  265.43 33.02 0 bottom
R227  10  [R0603]  222.83 53.57 180 top
R228  10  [R0603]  254 67.31 0 top
R229  0  [R0603]  185.29 87 0 top
R230  10K  [R0603]  182.25 87 180 top
R231  0  [R0603]  177.93 78.97 0 top
R232  0  [R0603]  167.01 88.9 0 top
R233  0  [R0603]  207.39 25.78 270 bottom
R234  0  [R0603]  157.35 23.11 270 bottom
R235  TBD0603  [R0603]  205.86 10.11 90 bottom
R236  TBD0603  [R0603]  205.86 13.24 90 bottom
R237  TBD0603  [R0603]  205.86 16.37 90 bottom
R238  TBD0603  [R0603]  205.86 19.49 90 bottom
R239  TBD0603  [R0603]  205.86 22.62 90 bottom
R240  0  [R0603]  205.86 25.75 90 bottom
R241  TBD0603  [R0603]  155.69 7.44 90 bottom
R242  TBD0603  [R0603]  155.69 10.57 90 bottom
R243  TBD0603  [R0603]  155.69 13.7 90 bottom
R244  TBD0603  [R0603]  155.69 16.83 90 bottom
R245  TBD0603  [R0603]  155.69 19.95 90 bottom
R246  0  [R0603]  155.69 23.08 90 bottom
R247  1K  [R0603]  207.52 19.56 270 bottom
R248  1K  [R0603]  157.24 16.84 270 bottom
R249  0  [R0603]  203.96 25.78 270 bottom
R250  0  [R0603]  153.92 23.11 270 bottom
R251  TBD0603  [R0603]  202.43 10.11 90 bottom
R252  TBD0603  [R0603]  202.43 13.24 90 bottom
R253  TBD0603  [R0603]  202.43 16.37 90 bottom
R254  TBD0603  [R0603]  202.43 19.49 90 bottom
R255  TBD0603  [R0603]  202.43 22.62 90 bottom
R256  0  [R0603]  202.43 25.75 90 bottom
R257  TBD0603  [R0603]  152.39 7.44 90 bottom
R258  TBD0603  [R0603]  152.39 10.57 90 bottom
R259  TBD0603  [R0603]  152.39 13.7 90 bottom
R260  TBD0603  [R0603]  152.39 16.83 90 bottom
R261  TBD0603  [R0603]  152.39 19.95 90 bottom
R262  0  [R0603]  152.39 23.08 90 bottom
R263  1K  [R0603]  203.97 19.51 270 bottom
R264  1K  [R0603]  153.94 16.84 270 bottom
R265  0  [R0603]  200.66 25.78 270 bottom
R266  0  [R0603]  150.5 22.99 270 bottom
R267  TBD0603  [R0603]  199.12 10.11 90 bottom
R268  TBD0603  [R0603]  199.12 13.24 90 bottom
R269  TBD0603  [R0603]  199.12 16.37 90 bottom
R270  TBD0603  [R0603]  199.12 19.49 90 bottom
R271  TBD0603  [R0603]  199.12 22.62 90 bottom
R272  0  [R0603]  199.12 25.75 90 bottom
R273  TBD0603  [R0603]  148.96 7.32 90 bottom
R274  TBD0603  [R0603]  148.96 10.44 90 bottom
R275  TBD0603  [R0603]  148.96 13.57 90 bottom
R276  TBD0603  [R0603]  148.96 16.7 90 bottom
R277  TBD0603  [R0603]  148.96 19.83 90 bottom
R278  0  [R0603]  148.96 22.96 90 bottom
R279  1K  [R0603]  200.67 19.51 270 bottom
R280  1K  [R0603]  150.51 16.72 270 bottom
R281  0  [R0603]  197.23 25.78 270 bottom
R282  0  [R0603]  147.07 22.99 270 bottom
R283  TBD0603  [R0603]  195.7 10.11 90 bottom
R284  TBD0603  [R0603]  195.7 13.24 90 bottom
R285  TBD0603  [R0603]  195.7 16.37 90 bottom
R286  TBD0603  [R0603]  195.7 19.49 90 bottom
R287  TBD0603  [R0603]  195.7 22.62 90 bottom
R288  0  [R0603]  195.7 25.75 90 bottom
R289  TBD0603  [R0603]  145.53 7.32 90 bottom
R290  TBD0603  [R0603]  145.53 10.44 90 bottom
R291  TBD0603  [R0603]  145.53 13.57 90 bottom
R292  TBD0603  [R0603]  145.53 16.7 90 bottom
R293  TBD0603  [R0603]  145.53 19.83 90 bottom
R294  0  [R0603]  145.53 22.96 90 bottom
R295  1K  [R0603]  197.24 19.51 270 bottom
R296  1K  [R0603]  147.08 16.72 270 bottom
R297  0  [R0603]  193.93 25.78 270 bottom
R298  0  [R0603]  143.76 22.99 270 bottom
R299  TBD0603  [R0603]  192.39 10.11 90 bottom
R300  TBD0603  [R0603]  192.39 13.24 90 bottom
R301  TBD0603  [R0603]  192.39 16.37 90 bottom
R302  TBD0603  [R0603]  192.39 19.49 90 bottom
R303  TBD0603  [R0603]  192.39 22.62 90 bottom
R304  0  [R0603]  192.39 25.75 90 bottom
R305  TBD0603  [R0603]  142.23 7.32 90 bottom
R306  TBD0603  [R0603]  142.23 10.44 90 bottom
R307  TBD0603  [R0603]  142.23 13.57 90 bottom
R308  TBD0603  [R0603]  142.23 16.7 90 bottom
R309  TBD0603  [R0603]  142.23 19.83 90 bottom
R310  0  [R0603]  142.23 22.96 90 bottom
R311  1K  [R0603]  193.94 19.51 270 bottom
R312  1K  [R0603]  143.78 16.72 270 bottom
R313  10K  [R1206]  198.35 87.6 90 top
R314  0  [R0603]  200.38 83.92 270 top
R315  0  [R0603]  170.05 90.93 0 top
R316  0  [R0603]  170.05 89.41 0 top
R317  10K  [R1206]  175.39 90.93 270 top
R318  10K  [R1206]  172.85 90.93 270 top
R319  120  [R0402]  201.27 90.65 180 top
R320  0  [R0603]  194.06 80.57 0 top
R321  0  [R0603]  194.56 88.77 90 top
R322  0  [R0603]  188.85 85.04 90 top
R323  0  [R0603]  195.33 84.07 180 top
R324  0  [R0603]  196.22 88.9 270 top
R325  120  [R0603]  191.9 16.38 180 top
R326  120  [R0603]  191.9 8.76 180 top
R327  120  [R0603]  191.9 10.67 180 top
R328  120  [R0603]  191.9 14.48 180 top
R329  120  [R0603]  191.9 20.19 180 top
R330  0  [R0603]  171.58 14.99 180 top
R331  0  [R0603]  171.58 13.46 180 top
R332  1.2K  [R0603]  196.98 57.28 90 top
R333  1.2K  [R0603]  189.36 57.28 90 top
R334  1.2K  [R0603]  187.83 57.28 90 top
R335  1.2K  [R0603]  180.34 58.67 0 top
R336  1.2K  [R0603]  186.31 57.28 90 top
R337  0  [R0603]  78.61 89.41 90 top
R338  0  [R0603]  101.09 20.07 180 top
R339  0  [R0603]  6.73 88.39 90 top
R340  0  [R0603]  159.77 90.42 90 top
R341  200  [R0603]  161.42 90.42 90 top
R342  0  [R0603]  158.12 90.42 90 top
R343  0  [R0603]  40.13 36.58 90 top
R344  0  [R0603]  119.38 36.32 90 top
R345  0  [R0603]  224.51 44.83 90 top
R346  10K  [R1206]  207.14 60.07 180 top
R347  10K  [R1206]  207.14 57.66 180 top
R348  10K  [R1206]  207.14 52.83 180 top
R349  10K  [R1206]  207.14 55.24 180 top
R350  0  [R0603]  192.41 57.28 90 top
R351  0  [R0603]  193.93 57.28 90 top
R352  0  [R0603]  195.45 57.28 90 top
R353  0  [R0603]  201.55 57.28 90 top
R354  0  [R0603]  203.07 60.2 180 top
R355  0  [R0603]  198.5 57.28 90 top
R356  0  [R0603]  200.03 57.28 90 top
R357  0  [R0603]  203.07 61.72 180 top
R358  0  [R0603]  203.07 63.25 180 top
R359  0  [R0603]  203.07 64.77 180 top
R360  0  [R0603]  203.07 66.29 180 top
R361  0  [R0603]  203.07 69.34 180 top
R362  0  [R0603]  203.07 67.82 180 top
R363  0  [R0603]  203.07 73.91 180 top
R364  0  [R0603]  203.07 75.44 180 top
R365  0  [R0603]  183.26 57.28 90 top
R366  0  [R0603]  184.79 57.28 90 top
R367  0  [R0603]  180.34 61.72 0 top
R368  0  [R0603]  180.34 60.2 0 top
R369  0  [R0603]  180.34 63.25 0 top
R370  0  [R0603]  190.88 57.28 90 top
R371  0  [R0603]  193.78 76.15 270 top
R372  0  [R0603]  180.34 64.9 0 top
R373  0  [R0603]  203.07 72.39 180 top
R374  0  [R0603]  203.07 70.87 180 top
R375  0.0001  [RSML3307W787H124_6FS]  317.62 50.8 90 top
R376  0  [R0603]  207.52 16.48 90 top
R377  33  [R5329]  234.95 38.73 180 bottom
R378  33  [R5329]  234.95 30.48 180 bottom
R379  33  [R5329]  234.95 46.99 180 bottom
R380  10  [R0603]  254 92.33 0 top
R381  0  [R0603]  181.53 78.31 0 top
R382  0  [R0603]  181.53 76.68 0 top
R383  10  [R0603]  290.83 35.56 0 top
R384  10  [R0603]  290.83 27.3 0 bottom
R385  10  [R0603]  290.83 8.89 0 top
R386  10  [R0603]  281.31 75.56 0 bottom
R387  10  [R0603]  281.31 83.19 0 top
R388  10  [R0603]  281.31 57.78 0 top
R389  43K  [R0805]  296.67 95.5 180 top
R390  1.24MEG  [R0805]  219.33 55.88 0 bottom
R391  43K  [R0805]  216.54 56.51 270 bottom
R392  0  [R0603]  101.09 18.41 180 top
R393  43K  [R0805]  213.61 14.48 180 top
R394  1.24MEG  [R0805]  217.17 14.48 180 top
R395  43K  [R0805]  221.36 35.69 180 bottom
R396  1.24MEG  [R0805]  225.04 35.69 180 bottom
R397  1.24MEG  [R0805]  293.12 95.5 180 top
R398  1K  [R0603]  192.02 52.07 90 top
RT1  10K  [R0603H35]  181.48 28.32 90 top
RT2  10K  [R0603H35]  176.53 28.32 270 top
S1  B3U-1000P  [SWSML118W98H69]  166.01 91.44 180 top
T1  7490100111  [TSML510W280H215]  27.94 25.65 0 top
T2  7490100111  [TSML510W280H215]  108.5 26.29 0 top
T3  7490100111  [TSML510W280H215]  163.32 32.77 180 top
T4  750312367  [TSML400W295H340]  165.1 57.02 180 top
T5  7490100111  [TSML510W280H215]  177.95 39.65 0 top
TP1  TP_VIA  [TPC63D35]  6.73 91.19 0 top
TP2  TP_VIA  [TPC63D35]  37.59 27.18 270 top
TP3  TP_VIA  [TPC63D35]  85.22 84.07 0 top
TP4  TP_VIA  [TPC63D35]  117.26 27.18 270 top
TP5  TESTPAD  [PAD160T100BR90]  201.3 78.99 0 top
TP6  TESTPAD  [PAD160T100BR90]  212.24 66.4 0 top
TP7  TP_VIA  [TPC63D35]  139.55 5.97 90 top
TP8  TP_VIA  [TPC63D35]  170.43 71.63 180 top
TP9  2501-2-00-80-00-00-07-0  [CNMILLMAX2501]  286.94 95.53 180 top
TP10  575-4  [CNBANANAD312LD203]  279.4 95.63 180 top
TP11  2501-2-00-80-00-00-07-0  [CNMILLMAX2501]  221.87 94.87 90 top
TP12  575-4  [CNBANANAD312LD203]  228.98 94.87 0 top
TP13  2501-2-00-80-00-00-07-0  [CNMILLMAX2501]  302.26 38.73 90 top
TP14  TESTPAD  [PAD160T100BR90]  212.17 71.4 0 top
TP15  TESTPAD  [PAD160T100BR90]  211.96 76.43 0 top
TP16  575-4  [CNBANANAD312LD203]  212.6 6.48 0 top
U1  ADBMS6830MWCSWZ  [QFP80_12X12_PAD5_81X5_81]  42.8 49.28 90 top
U2  24LC02B-E/SN  [SO8]  60.33 32.13 90 top
U3  ADBMS6830MWCSWZ  [QFP80_12X12_PAD5_81X5_81]  122.47 49.28 90 top
U4  24LC02B-E/SN  [SO8]  140 32.13 90 top
U5  ADBMS2950WCCSZ  [QFN48_7X7_PAD4_8X4_8]  178.94 15.37 90 top
U6  LTC3639EMSE#PBF  [MSOP16_PAD2_845X1_651_12P]  134.34 9.27 0 top
U7  24LC02B-E/SN  [SO8]  154.94 4.7 270 top
U8  ADUM225N1BRIZ  [SO8WB_A]  208.1 41.81 0 top
U9  LT8303IS5#TRMPBF  [TSOT-5]  166.42 42.04 0 top
U10  ADBMS6822WCCSZ  [QFN32_5X5_PAD2_1X2_1]  197.23 46.33 180 top
U11  LTC7001IMSE#WPBF  [MSOP10_PAD1_88X1_68]  218.67 31.55 270 top
U12  LTC7001IMSE#WPBF  [MSOP10_PAD1_88X1_68]  219.35 51.18 0 top
U13  LTC7001IMSE#WPBF  [MSOP10_PAD1_88X1_68]  220.98 41.27 0 top
U14  MAX20337AEFT+  [DFN6_F61A1F_1]  184.89 84.91 0 top
U15  MAX25301AATB/V+  [DFN10_3X3_PAD2_3X1_5]  182.25 81.03 90 top
U16  ADP151ACBZ-1.8-R7  [WLCSP4H26]  168.02 85.22 270 top
U17  ADP151WACBZ-1.2  [WLCSP4H26]  168.02 80.26 270 top
U18  ADP151ACBZ-1.1  [WLCSP4H26]  168.02 75.31 270 top
U19  LTC2875HDD#PBF  [DFN8_3X3_PAD2_38X1_65]  201.52 87.86 0 top
U20  MAX6071AAUT33+T  [SOT23_6-3]  191.64 85.22 90 top
U21  MAX3207EAUT+  [SOT23_6]  184.73 90.68 270 top
U22  MAX32690GTK+  [QFN68_8X8_PAD6_25X6_25]  192.02 67.82 0 top
Y1  32.768KHZ  [YSML65W41H20]  187.96 74.68 180 top
Y2  32MHZ  [YSML63W47H14]  180.72 68.33 270 top

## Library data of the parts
C1-C16 C25-C40 C67 C68 C79-C86 C93-C110 C119-C134 C161 C162 C173-C181 C187-C191 C209 C210 C216 C217 C296-C335 C337-C342 = CAP: User Part Number: UPN; Tolerance: 10; alternate symbols: (C0603); part number: CAP_SM-10NF,100V,10,E044216,C0603; tolerance: 10
C17-C24 C41-C64 C111-C118 C135-C158 = CAP: User Part Number: UPN; Tolerance: 10; alternate symbols: (C0603); part number: CAP_SM-0.22UF,50V,10,E015565,C0603; tolerance: 10
C65 C66 C70 C159 C160 C164 C194-C196 C231 C237 C243 C269 C272 C273 C275-C279 C281-C286 = CAP: User Part Number: UPN; Tolerance: 10; alternate symbols: (C0603); part number: CAP_SM-1UF,16V,10,E020596,C0603; tolerance: 10
C69 C71-C78 C91 C92 C163 C165-C172 C185 C186 C200 C202 C207 C208 C211 C212 C218 C219 C224-C229 C258-C267 = CAP: User Part Number: UPN; Tolerance: 10; alternate symbols: (C0603); part number: CAP_SM-0.1UF,25V,10,E031923,C0603; tolerance: 10
C87-C90 C182-C184 C203-C206 C220-C223 C336 = CAP: User Part Number: UPN; Tolerance: 5; alternate symbols: (C0402); part number: CAP_SM-300PF,50V,5,E034423,C0402; tolerance: 5
C192 C193 = CAP: User Part Number: UPN; Tolerance: 10; alternate symbols: (C0805); part number: CAP_SM-33NF,50V,10,E056507,C0805; tolerance: 10
C197 C230 C236 C242 = CAPP: User Part Number: UPN; Tolerance: 20; alternate symbols: (CPLSMSQ327H413); part number: CAPP_SM-22UF,100V,20,E026358,CPLSMSQ327H413; tolerance: 20
C198 = CAP: User Part Number: UPN; Tolerance: 10; alternate symbols: (C0603); part number: CAP_SM-47NF,100V,10,E044215,C0603; tolerance: 10
C199 C232 C233 C235 C238 C239 C241 C244-C246 = CAP: User Part Number: UPN; Tolerance: 10; alternate symbols: (C1825H65); part number: CAP_SM-1UF,250V,10,E016914,C1825H65; tolerance: 10
C201 = CAP: Tolerance: 20; User Part Number: UPN; alternate symbols: (C1210H110); part number: CAP_SM-100UF,10V,20,E063422,C1210H110; tolerance: 20
C214 = CAP: Tolerance: 10; User Part Number: UPN; alternate symbols: (C1210H87); part number: CAP_SM-4.7UF,100V,10,E023932,C1210H87; tolerance: 10
C215 = CAP: User Part Number: UPN; Tolerance: 20; alternate symbols: (C2220H98); part number: CAP_SM-47UF,25V,20,E044247,C2220H98; tolerance: 20
C234 C240 C247 = CAP: User Part Number: UPN; Tolerance: 10; alternate symbols: (C1206); part number: CAP_SM-0.1UF,250V,10,E015837,C1206; tolerance: 10
C248 C270 C271 C289 C291 = CAP: User Part Number: UPN; Tolerance: 10; alternate symbols: (C0603); part number: CAP_SM-0.1UF,16V,10,E011547,C0603; tolerance: 10
C249 C251 = CAP: User Part Number: UPN; Tolerance: 20; alternate symbols: (C0603); part number: CAP_SM-10UF,25V,20,E035949,C0603; tolerance: 20
C250 = CAP: Tolerance: 10; User Part Number: UPN; alternate symbols: (C1210H87); part number: CAP_SM-0.047UF,630V,10,E014540,C1210H87; tolerance: 10
C252-C257 = CAP: User Part Number: UPN; Tolerance: 10; alternate symbols: (C1206); part number: CAP_SM-1UF,50V,10,E021800,C1206; tolerance: 10
C268 = CAP: Tolerance: 10; User Part Number: UPN; alternate symbols: (C0805H53); part number: CAP_SM-2.2UF,25V,10,E025703,C0805H53; tolerance: 10
C274 = CAP: User Part Number: UPN; Tolerance: 10; alternate symbols: (C0402); part number: CAP_SM-4.7NF,16V,10,E042800,C0402; tolerance: 10
C280 = CAP: Tolerance: 10; User Part Number: UPN; alternate symbols: (C1206H71); part number: CAP_SM-10UF,16V,10,E031777,C1206H71; tolerance: 10
C287 = CAP: User Part Number: UPN; Tolerance: 2; alternate symbols: (C1206); part number: CAP_SM-0.1UF,25V,2,E012519,C1206; tolerance: 2
C288 = CAP: User Part Number: UPN; Tolerance: 10; alternate symbols: (C0805H55); part number: CAP_SM-1UF,35V,10,E063716,C0805H55; tolerance: 10
C290 = CAP: User Part Number: UPN; Tolerance: 10; alternate symbols: (C0402); part number: CAP_SM-10NF,25V,10,E046235,C0402; tolerance: 10
C292-C295 = CAP: User Part Number: UPN; Tolerance: 5; alternate symbols: (C0402); part number: CAP_SM-12PF,50V,5,E034633,C0402; tolerance: 5
C343-C359 = CAP: User Part Number: UPN; Tolerance: 10; alternate symbols: (C0603); part number: CAP_SM-0.22UF,25V,10,E022876,C0603; tolerance: 10
D1-D16 = DIOZNR_V3: Tolerance: N/A; User Part Number: UPN; alternate symbols: (SOD323-5); part number: DIOZNR_V3_SM-SD12C-01FTG,12V,N/A,E041545,SOD323-5; tolerance: N/A
D17 = DIOZNR: User Part Number: UPN; Tolerance: N/A; alternate symbols: (SOD123FL); part number: DIOZNR_SM-TPSMF4L28A,28V,N/A,E033310,SOD123FL; tolerance: N/A
D18 = DIOSCHOTTKY: Tolerance: N/A; User Part Number: UPN; alternate symbols: (SOD123F); part number: DIOSCHOTTKY_SM-PMEG10010ELRX,100V,N/A,E027874,SOD123F; tolerance: N/A
D19 = DIOSCHOTTKY: User Part Number: UPN; Tolerance: N/A; alternate symbols: (SOD128); part number: DIOSCHOTTKY_SM-PMEG6030EP,115,60V,N/A,E052764,SOD128; tolerance: N/A
D20 = DIOZNR: Tolerance: 2.13; User Part Number: UPN; alternate symbols: (SOD523_B); part number: DIOZNR_SM-EDZVFHT2R15B,15V,2.13,E048713,SOD523_B; tolerance: 2.13
D21 D24 = DIO: User Part Number: UPN; Tolerance: N/A; alternate symbols: (SOD123-2); part number: DIO_SM-1N4148W-7-F,100V,N/A,E018902,SOD123-2; tolerance: N/A
D22 D23 = DIOTVS: User Part Number: UPN; Tolerance: N/A; alternate symbols: (SMA-2); part number: DIOTVS_SM-SMAT70A-13-F,70V,N/A,E032827,SMA-2; tolerance: N/A
D25-D32 D34-D49 D51-D58 = DIO3P_V14: User Part Number: UPN; Tolerance: N/A; alternate symbols: (SOT23_B); part number: DIO3P_V14_SM-SBAV70LT3G,100V,N/A,E057069,SOT23_B; tolerance: N/A
D33 D50 D66 = DIOTVS: User Part Number: UPN; Tolerance: N/A; alternate symbols: (DO214AA_A); part number: DIOTVS_SM-SMBJ75A-13-F,75V,N/A,E057070,DO214AA_A; tolerance: N/A
D59-D65 D68-D74 = DIOTVS: User Part Number: UPN; Tolerance: N/A; alternate symbols: (DO214AC_A); part number: DIOTVS_SM-SMAJ7.0A,7V,N/A,E061256,DO214AC_A; tolerance: N/A
D67 = DIOTVS_BIDIR: Tolerance: N/A; User Part Number: UPN; alternate symbols: (DTH819L350W350LD52_BIDIR); part number: DIOTVS_BIDIR_TH-30KPA120CA,120V,N/A,E066299,DTH819L350W350LD52_BIDIR; tolerance: N/A
DS1-DS6 = DIOLED: Tolerance: N/A; User Part Number: UPN; alternate symbols: (LED0603-2); part number: DIOLED_SM-SML-D13FWT86C,2.1V,N/A,E040424,LED0603-2; tolerance: N/A
E1-E6 = FERRITE: User Part Number: UPN; Tolerance: 25; alternate symbols: (L0603); part number: FERRITE_SM-2.2KOHM AT 100MEGHZ,25,E041674,L0603; tolerance: 25
E7 E8 = FERRITE: Tolerance: 25; User Part Number: UPN; alternate symbols: (L1206-3); part number: FERRITE_SM-1KOHM AT 100MEGHZ,25,E020367,L1206-3; tolerance: 25
F1 = FSFUSE: User Part Number: UPN; Tolerance: N/A; alternate symbols: (FSML484W177H185); part number: FSFUSE_SM-100A,72VDC,E051575,FSML484W177H185; tolerance: N/A
L1 = IND: Tolerance: 30; User Part Number: UPN; alternate symbols: (LSML402W394H201); part number: IND_SM-220UH,30,E047996,LSML402W394H201; tolerance: 30
L2 = IND: Tolerance: 25; User Part Number: UPN; alternate symbols: (L1206); part number: IND_SM-2000OHMS,25,E002365,L1206; tolerance: 25
